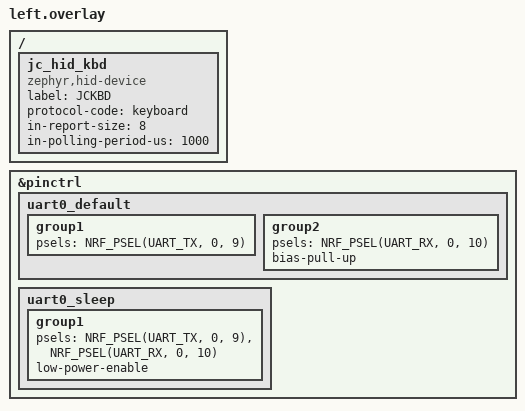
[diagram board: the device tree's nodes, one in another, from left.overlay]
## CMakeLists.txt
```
cmake_minimum_required(VERSION 3.20.0)

if(JC_LEFT)
  list(APPEND EXTRA_DTC_OVERLAY_FILE "${CMAKE_CURRENT_LIST_DIR}/left.overlay")
  list(APPEND EXTRA_CONF_FILE "${CMAKE_CURRENT_LIST_DIR}/left.conf")
endif()
list(APPEND EXTRA_DTC_OVERLAY_FILE "${CMAKE_CURRENT_LIST_DIR}/clock_rc.overlay")
list(APPEND EXTRA_CONF_FILE "${CMAKE_CURRENT_LIST_DIR}/clock_rc.conf")
if(NOT JC_LEFT)
  list(APPEND EXTRA_DTC_OVERLAY_FILE "${CMAKE_CURRENT_LIST_DIR}/right.overlay")
  list(APPEND EXTRA_CONF_FILE "${CMAKE_CURRENT_LIST_DIR}/usb_name_right.conf")
endif()
list(APPEND EXTRA_CONF_FILE "${CMAKE_CURRENT_LIST_DIR}/tx_power.conf")

if(NOT DEFINED JC_OUT)
  set(JC_OUT "${CMAKE_CURRENT_LIST_DIR}/out")
endif()
if(JC_OUT)
  if(JC_LEFT)
    set(jc_uf2 "${JC_OUT}/xd2joy_LEFT.uf2")
  else()
    set(jc_uf2 "${JC_OUT}/xd2joy_RIGHT.uf2")
  endif()
  set_property(GLOBAL APPEND PROPERTY extra_post_build_commands
    COMMAND ${CMAKE_COMMAND} -E copy ${CMAKE_BINARY_DIR}/zephyr/zephyr.uf2 ${jc_uf2}
    COMMAND ${CMAKE_COMMAND} -E echo Firmware copied to ${jc_uf2})
endif()

find_package(Zephyr REQUIRED HINTS $ENV{ZEPHYR_BASE})
project(xd2joy)

file(READ "${ZEPHYR_BASE}/include/zephyr/bluetooth/hci_types.h" jc_hci)
string(REGEX MATCH "#define[ \t]+BT_HCI_LE_INTERVAL_MIN[ \t]+0x0004" jc_floor "${jc_hci}")
if(NOT jc_floor)
  message(FATAL_ERROR "Zephyr patch 1 is missing: BT_HCI_LE_INTERVAL_MIN in "
                      "include/zephyr/bluetooth/hci_types.h is not 0x0004 -- see "
                      "ZEPHYR_PATCHES.md at the top of this repository")
endif()

foreach(jc_patched
    subsys/bluetooth/controller/ll_sw/nordic/lll/lll_scan.c
    subsys/bluetooth/controller/ll_sw/ull_llcp_conn_upd.c)
  file(READ "${ZEPHYR_BASE}/${jc_patched}" jc_src)
  string(FIND "${jc_src}" "conn window patch" jc_at)
  if(jc_at EQUAL -1)
    message(FATAL_ERROR "Zephyr patch 2 is missing from ${jc_patched} -- see "
                        "ZEPHYR_PATCHES.md at the top of this repository")
  endif()
endforeach()
zephyr_compile_definitions(JC_CONN_WIN_OFFSET=4 JC_CONN_WIN_SIZE=3)

target_sources(app PRIVATE
    src/chip_addr.c
    src/console_keep.c
    src/main.c
    src/hci_user_ext.c)
target_include_directories(app PRIVATE
    ${ZEPHYR_BASE}/subsys/bluetooth/controller
    ${ZEPHYR_BASE}/subsys/bluetooth/controller/ll_sw/nordic)
target_include_directories(app PRIVATE ${ZEPHYR_BASE}/subsys/bluetooth)
zephyr_include_directories(src)

if(JC_LEFT)
  target_compile_definitions(app PRIVATE JC_LEFT=1)
  target_sources(app PRIVATE src/usb_dev.c)
endif()
```

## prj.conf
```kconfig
CONFIG_BT=y
CONFIG_BT_PERIPHERAL=y
CONFIG_BT_DEVICE_NAME="Joy-Con 2 (R)"

CONFIG_BT_L2CAP_TX_MTU=512
CONFIG_BT_BUF_ACL_RX_SIZE=520
CONFIG_BT_BUF_ACL_TX_SIZE=251
CONFIG_BT_ATT_PREPARE_COUNT=2

CONFIG_BT_GATT_SERVICE_CHANGED=n
CONFIG_BT_GATT_CACHING=n

CONFIG_PRINTK=y

CONFIG_BT_GAP_PERIPHERAL_PREF_PARAMS=n

CONFIG_BT_HCI_VS=y
CONFIG_BT_DEVICE_NAME="Joy-Con 2 (R)"

CONFIG_BT_CTLR_TX_PWR_PLUS_4=y

CONFIG_BT_CTLR_CONN_INTERVAL_LOW_LATENCY=n
CONFIG_BT_CONN_PARAM_ANY=y
CONFIG_BT_CTLR_ADVANCED_FEATURES=y
CONFIG_BT_GAP_AUTO_UPDATE_CONN_PARAMS=n

CONFIG_BT_SMP=y

CONFIG_BT_GATT_CLIENT=y
CONFIG_BT_GATT_AUTO_UPDATE_MTU=n

CONFIG_BT_CTLR_DATA_LENGTH_MAX=251

CONFIG_BT_CTLR_USER_EXT=y
CONFIG_BT_CTLR_USER_CPR_INTERVAL_MIN=y

CONFIG_BT_CENTRAL=y
CONFIG_BT_OBSERVER=y
CONFIG_BT_MAX_CONN=2
CONFIG_BT_MAX_PAIRED=2
CONFIG_BT_GATT_AUTO_DISCOVER_CCC=y

CONFIG_BT_SMP_ENFORCE_MITM=n

CONFIG_BT_SMP_SC_PAIR_ONLY=n

CONFIG_LOG=n
CONFIG_BT_SMP_LOG_LEVEL_DBG=n

CONFIG_BT_SCAN_WITH_IDENTITY=y

CONFIG_BT_RX_STACK_SIZE=3072
CONFIG_MAIN_STACK_SIZE=2048
CONFIG_SYSTEM_WORKQUEUE_STACK_SIZE=3072

CONFIG_THREAD_ANALYZER=n
CONFIG_RESET_ON_FATAL_ERROR=n

CONFIG_SERIAL=y
CONFIG_UART_INTERRUPT_DRIVEN=y

CONFIG_BT_ATT_TX_COUNT=10

CONFIG_BT_BUF_ACL_TX_COUNT=12
CONFIG_BT_L2CAP_TX_BUF_COUNT=12
CONFIG_BT_BUF_EVT_RX_COUNT=16

CONFIG_BT_SETTINGS=y
CONFIG_FLASH=y
CONFIG_FLASH_MAP=y
CONFIG_FLASH_PAGE_LAYOUT=y
CONFIG_NVS=y
CONFIG_SETTINGS=y

CONFIG_MPU_ALLOW_FLASH_WRITE=y
```

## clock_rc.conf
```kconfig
CONFIG_CLOCK_CONTROL_NRF_K32SRC_RC_CALIBRATION=y

CONFIG_CLOCK_CONTROL_NRF_CALIBRATION_PERIOD=4000
CONFIG_CLOCK_CONTROL_NRF_CALIBRATION_MAX_SKIP=1
CONFIG_CLOCK_CONTROL_NRF_CALIBRATION_TEMP_DIFF=2
```

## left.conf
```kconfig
CONFIG_CDC_ACM_SERIAL_INITIALIZE_AT_BOOT=n

CONFIG_USBD_HID_SUPPORT=y
```

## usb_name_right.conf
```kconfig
CONFIG_CDC_ACM_SERIAL_MANUFACTURER_STRING="XD2Joy"
CONFIG_CDC_ACM_SERIAL_PRODUCT_STRING="XD2Joy (right)"
```

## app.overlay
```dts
&uicr {
	nfct-pins-as-gpios;
};

#include <zephyr/dt-bindings/pinctrl/nrf-pinctrl.h>

&pinctrl {
	uart0_default: uart0_default {
		group1 {
			psels = <NRF_PSEL(UART_TX, 0, 9)>;
		};
		group2 {
			psels = <NRF_PSEL(UART_RX, 0, 10)>;
			bias-pull-up;
		};
	};

	uart0_sleep: uart0_sleep {
		group1 {
			psels = <NRF_PSEL(UART_TX, 0, 9)>,
				<NRF_PSEL(UART_RX, 0, 10)>;
			low-power-enable;
		};
	};
};
```

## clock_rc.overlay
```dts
&lfclk {
	k32src = "rc";
	k32src-accuracy-ppm = <500>;
};
```

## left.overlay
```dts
#include <zephyr/dt-bindings/pinctrl/nrf-pinctrl.h>

&pinctrl {
	uart0_default: uart0_default {
		group1 {
			psels = <NRF_PSEL(UART_TX, 0, 9)>;
		};
		group2 {
			psels = <NRF_PSEL(UART_RX, 0, 10)>;
			bias-pull-up;
		};
	};

	uart0_sleep: uart0_sleep {
		group1 {
			psels = <NRF_PSEL(UART_TX, 0, 9)>,
				<NRF_PSEL(UART_RX, 0, 10)>;
			low-power-enable;
		};
	};
};

/ {
	jc_hid_kbd: jc_hid_kbd {
		compatible = "zephyr,hid-device";
		label = "JCKBD";
		protocol-code = "keyboard";
		in-report-size = <8>;
		in-polling-period-us = <1000>;
	};
};
```

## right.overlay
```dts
#include <zephyr/dt-bindings/pinctrl/nrf-pinctrl.h>

&pinctrl {
	uart0_default: uart0_default {
		group1 {
			psels = <NRF_PSEL(UART_TX, 1, 4)>;
		};
		group2 {
			psels = <NRF_PSEL(UART_RX, 1, 6)>;
			bias-pull-up;
		};
	};

	uart0_sleep: uart0_sleep {
		group1 {
			psels = <NRF_PSEL(UART_TX, 1, 4)>,
				<NRF_PSEL(UART_RX, 1, 6)>;
			low-power-enable;
		};
	};
};

&i2c1 {
	status = "disabled";
};
```

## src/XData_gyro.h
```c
#pragma once

#define ROT_PLAY_AT 0x0D
#define ROT_PLAY_LEN 43

static const uint8_t ROT_PLAY[89][ROT_PLAY_LEN] = {
  { 0xFF, 0x00, 0x28, 0x76, 0xB9, 0x02, 0x0F, 0x83, 0x76, 0x8F, 0x56, 0x48, 0x09, 0x59, 0xAA, 0x02, 0x05, 0xF8, 0x05, 0xD7, 0x4F, 0x02, 0xC0, 0xF4, 0xBF, 0xFC, 0x3F, 0x0B, 0xF8, 0x05, 0xF1, 0xA7, 0x01, 0x40, 0xFF, 0xFF, 0xFD, 0x9F, 0x0B, 0x00, 0x0C, 0xDA, 0x9F },
  { 0xFF, 0x00, 0x28, 0xA0, 0xA9, 0x02, 0x0F, 0x63, 0x84, 0x8F, 0xAA, 0x43, 0x89, 0xEF, 0xA9, 0x72, 0x05, 0x04, 0x06, 0xE8, 0x0F, 0x01, 0x40, 0xF4, 0x7F, 0xFD, 0xBF, 0x0A, 0x00, 0x06, 0xEE, 0x27, 0x01, 0x80, 0xFA, 0xFF, 0xFE, 0x1F, 0x0B, 0x00, 0x0C, 0xB8, 0x9F },
  { 0xFF, 0x00, 0x28, 0xCA, 0xA9, 0x02, 0x0F, 0x83, 0x8A, 0x8F, 0x46, 0x3E, 0x89, 0x8E, 0xA9, 0x92, 0x05, 0xF8, 0x05, 0xE0, 0xCF, 0x02, 0x40, 0xFD, 0x7F, 0xFC, 0x3F, 0x0B, 0x00, 0x06, 0xF4, 0xC7, 0x00, 0xC0, 0xFB, 0x9F, 0xFE, 0xBF, 0x0A, 0x08, 0x0C, 0xD4, 0x9F },
  { 0xFF, 0x00, 0x28, 0xF5, 0xB9, 0x02, 0x0F, 0x63, 0x94, 0x8F, 0x32, 0x38, 0x89, 0x16, 0xA9, 0x52, 0x05, 0xFC, 0x05, 0xE2, 0x0F, 0x04, 0x80, 0xFC, 0xBF, 0xFC, 0xFF, 0x0A, 0xF8, 0x05, 0xED, 0x07, 0x01, 0xE0, 0xFC, 0x7F, 0xFE, 0xBF, 0x0A, 0x08, 0x0C, 0xB6, 0x9F },
  { 0xFF, 0x00, 0x28, 0x1F, 0xAA, 0x02, 0x0F, 0xA3, 0x9C, 0x8F, 0x6E, 0x31, 0x09, 0x92, 0xA8, 0x42, 0x05, 0x08, 0x06, 0xE8, 0x8F, 0x02, 0xC0, 0xFA, 0xBF, 0xFC, 0x7F, 0x0B, 0x08, 0x06, 0xF4, 0xC7, 0x00, 0xA0, 0xFF, 0x3F, 0xFE, 0x5F, 0x0B, 0xF8, 0x0B, 0xCC, 0x9F },
  { 0xFF, 0x00, 0x28, 0x47, 0x8A, 0x02, 0x0F, 0x43, 0xAA, 0x8F, 0x5E, 0x2E, 0x89, 0x4C, 0xA8, 0x52, 0x05, 0xF4, 0x05, 0xDC, 0xCF, 0x01, 0x40, 0xF5, 0x3F, 0xFD, 0x7F, 0x0A, 0xF8, 0x05, 0xED, 0xA7, 0x00, 0xE0, 0xFA, 0x9F, 0xFE, 0xDF, 0x0A, 0x08, 0x0C, 0xCC, 0x9F },
  { 0xFF, 0x00, 0x28, 0x72, 0xBA, 0x02, 0x0F, 0x23, 0xB2, 0x8F, 0xCE, 0x27, 0x89, 0xC3, 0xA7, 0x72, 0x05, 0x04, 0x06, 0xEB, 0x4F, 0x02, 0x80, 0xFB, 0x7F, 0xFC, 0xFF, 0x0A, 0x00, 0x06, 0xF0, 0xC7, 0x00, 0xE0, 0xFC, 0x5F, 0xFE, 0xDF, 0x0A, 0xF0, 0x0B, 0xBA, 0x9F },
  { 0xFF, 0x00, 0x28, 0x9C, 0xAA, 0x02, 0x0F, 0x63, 0xB9, 0x8F, 0x62, 0x23, 0x89, 0x67, 0xA7, 0x52, 0x05, 0x00, 0x06, 0xDC, 0x0F, 0x02, 0xC0, 0xF7, 0xFF, 0xFC, 0xFF, 0x0A, 0x00, 0x06, 0xF1, 0xE7, 0x00, 0xC0, 0xFC, 0x7F, 0xFE, 0xFF, 0x0A, 0x10, 0x0C, 0xD6, 0x9F },
  { 0xFF, 0x00, 0x28, 0xC7, 0xBA, 0x02, 0x0F, 0x63, 0xC5, 0x8F, 0xBE, 0x1D, 0x89, 0xF3, 0xA6, 0x62, 0x05, 0x00, 0x06, 0xE6, 0xCF, 0x02, 0x40, 0xFA, 0xBF, 0xFC, 0xFF, 0x0A, 0x00, 0x06, 0xED, 0x47, 0x01, 0x40, 0xFB, 0x9F, 0xFE, 0x9F, 0x0A, 0x00, 0x0C, 0xBA, 0x9F },
  { 0xFF, 0x00, 0x28, 0xF1, 0xAA, 0x02, 0x0F, 0xC3, 0xCD, 0x8F, 0xB6, 0x16, 0x09, 0x76, 0xA6, 0x72, 0x05, 0x00, 0x06, 0xE4, 0x8F, 0x01, 0x80, 0xFC, 0xBF, 0xFC, 0x3F, 0x0B, 0x00, 0x06, 0xF4, 0x47, 0x01, 0xE0, 0xFE, 0x7F, 0xFE, 0x1F, 0x0B, 0x00, 0x0C, 0xCC, 0x9F },
  { 0xFF, 0x00, 0x28, 0x1B, 0xAB, 0x02, 0x0F, 0xA3, 0xD8, 0x8F, 0x76, 0x13, 0x09, 0x33, 0xA6, 0x52, 0x05, 0xFC, 0x05, 0xE2, 0xCF, 0x01, 0xC0, 0xF6, 0xFF, 0xFC, 0xFF, 0x0A, 0x00, 0x06, 0xEF, 0x07, 0x01, 0xA0, 0xFB, 0x3F, 0xFE, 0xDF, 0x0A, 0x08, 0x0C, 0xC4, 0x9F },
  { 0xFF, 0x00, 0x28, 0x45, 0xAB, 0x02, 0x0F, 0x23, 0xE1, 0x8F, 0x26, 0x0D, 0x09, 0xAB, 0xA5, 0x72, 0x05, 0x08, 0x06, 0xE9, 0xCF, 0x02, 0x80, 0xFC, 0xBF, 0xFC, 0xFF, 0x0A, 0x08, 0x06, 0xF3, 0xE7, 0x00, 0x80, 0xFC, 0x5F, 0xFE, 0x9F, 0x0A, 0x00, 0x0C, 0xBE, 0x9F },
  { 0xFF, 0x00, 0x28, 0x70, 0xBB, 0x02, 0x0F, 0xC3, 0xE7, 0x8F, 0x86, 0x06, 0x09, 0x28, 0xA5, 0x42, 0x05, 0x00, 0x06, 0xDE, 0xCF, 0x02, 0x00, 0xFB, 0x3F, 0xFC, 0x3F, 0x0B, 0x00, 0x06, 0xF3, 0x67, 0x01, 0xA0, 0xFE, 0x3F, 0xFE, 0x1F, 0x0B, 0x00, 0x0C, 0xCC, 0x9F },
  { 0xFF, 0x00, 0x28, 0x98, 0x8B, 0x02, 0x0F, 0x23, 0xF4, 0x8F, 0x36, 0x03, 0x09, 0xDE, 0xA4, 0x52, 0x05, 0x00, 0x06, 0xE5, 0x0F, 0x02, 0x40, 0xF7, 0x7F, 0xFD, 0xFF, 0x0A, 0xF8, 0x05, 0xEF, 0xE7, 0x00, 0x20, 0xFB, 0x7F, 0xFE, 0xBF, 0x0A, 0xF0, 0x0B, 0xC0, 0x9F },
  { 0xFF, 0x00, 0x28, 0xC2, 0xAB, 0x02, 0x0F, 0xA3, 0xFC, 0x8F, 0xBE, 0xFC, 0x08, 0x5F, 0xA4, 0x62, 0x05, 0xFC, 0x05, 0xE4, 0x0F, 0x02, 0x00, 0xFA, 0xBF, 0xFC, 0xFF, 0x0A, 0x08, 0x06, 0xF3, 0xA7, 0x00, 0x80, 0xFC, 0x7F, 0xFE, 0xFF, 0x0A, 0x10, 0x0C, 0xCA, 0x9F },
  { 0xFF, 0x00, 0x28, 0xED, 0xBB, 0x02, 0x0F, 0x63, 0x05, 0x90, 0x32, 0xF7, 0x88, 0xED, 0xA3, 0x72, 0x05, 0xFC, 0x05, 0xE2, 0x4F, 0x03, 0x40, 0xFB, 0x3F, 0xFD, 0x3F, 0x0B, 0xF8, 0x05, 0xEF, 0x47, 0x01, 0x00, 0xFD, 0x7F, 0xFE, 0xBF, 0x0A, 0xF0, 0x0B, 0xC2, 0x9F },
  { 0xFF, 0x00, 0x28, 0x17, 0xAC, 0x02, 0x0F, 0xC3, 0x0E, 0x90, 0x72, 0xF2, 0x08, 0x9A, 0xA3, 0x62, 0x05, 0x04, 0x06, 0xE6, 0xCF, 0x01, 0xC0, 0xFA, 0xBF, 0xFC, 0xFF, 0x0A, 0x00, 0x06, 0xF3, 0x47, 0x01, 0x20, 0xFD, 0x3F, 0xFE, 0xFF, 0x0A, 0x08, 0x0C, 0xC2, 0x9F },
  { 0xFF, 0x00, 0x28, 0x41, 0xAC, 0x02, 0x0F, 0xC3, 0x1A, 0x90, 0xF2, 0xEC, 0x88, 0x27, 0xA3, 0x72, 0x05, 0xFC, 0x05, 0xDD, 0x0F, 0x03, 0x00, 0xFA, 0xBF, 0xFC, 0xFF, 0x0A, 0x00, 0x06, 0xF1, 0x07, 0x01, 0x60, 0xFC, 0x3F, 0xFE, 0xFF, 0x0A, 0x08, 0x0C, 0xC6, 0x9F },
  { 0xFF, 0x00, 0x28, 0x6C, 0xBC, 0x02, 0x0F, 0x63, 0x22, 0x90, 0x56, 0xE8, 0x08, 0xC7, 0xA2, 0x82, 0x05, 0x04, 0x06, 0xE6, 0x0F, 0x02, 0x40, 0xFA, 0xFF, 0xFC, 0x3F, 0x0B, 0x00, 0x06, 0xF1, 0x87, 0x01, 0x40, 0xFE, 0x5F, 0xFE, 0xDF, 0x0A, 0xF8, 0x0B, 0xBE, 0x9F },
  { 0xFF, 0x00, 0x28, 0x96, 0xAC, 0x02, 0x0F, 0x83, 0x2E, 0x90, 0xA2, 0xE2, 0x88, 0x56, 0xA2, 0x52, 0x05, 0xFC, 0x05, 0xE1, 0x4F, 0x02, 0x80, 0xF6, 0xBF, 0xFC, 0xBF, 0x0A, 0x00, 0x06, 0xF1, 0xE7, 0x00, 0xC0, 0xFC, 0x7F, 0xFE, 0x1F, 0x0B, 0x08, 0x0C, 0xCE, 0x9F },
  { 0xFF, 0x00, 0x28, 0xC0, 0xAC, 0x02, 0x0F, 0x63, 0x38, 0x90, 0xAA, 0xDC, 0x08, 0xDF, 0xA1, 0x72, 0x05, 0x00, 0x06, 0xE2, 0x8F, 0x02, 0x80, 0xF9, 0x7F, 0xFC, 0xFF, 0x0A, 0x08, 0x06, 0xF0, 0x07, 0x01, 0x00, 0xFC, 0x5F, 0xFE, 0xFF, 0x0A, 0xF8, 0x0B, 0xBE, 0x9F },
  { 0xFF, 0x00, 0x28, 0xE9, 0x9C, 0x02, 0x0F, 0x23, 0x3F, 0x90, 0x92, 0xD7, 0x88, 0x78, 0xA1, 0x82, 0x05, 0x04, 0x06, 0xE4, 0xCF, 0x02, 0xC0, 0xFA, 0x7F, 0xFC, 0x3F, 0x0B, 0x00, 0x06, 0xF3, 0x47, 0x01, 0xA0, 0xFD, 0x5F, 0xFE, 0xDF, 0x0A, 0x10, 0x0C, 0xC8, 0x9F },
  { 0xFF, 0x00, 0x28, 0x13, 0xAD, 0x02, 0x0F, 0x23, 0x4D, 0x90, 0x2E, 0xD2, 0x08, 0x0B, 0xA1, 0x62, 0x05, 0xFC, 0x05, 0xDF, 0xCF, 0x01, 0x00, 0xF7, 0xFF, 0xFC, 0xFF, 0x0A, 0x00, 0x06, 0xEF, 0x47, 0x01, 0x60, 0xFB, 0x7F, 0xFE, 0xFF, 0x0A, 0x18, 0x0C, 0xC8, 0x9F },
  { 0xFF, 0x00, 0x28, 0x3D, 0xAD, 0x02, 0x0F, 0x43, 0x56, 0x90, 0x82, 0xCC, 0x88, 0x9A, 0xA0, 0x72, 0x05, 0x04, 0x06, 0xE6, 0x8F, 0x02, 0x80, 0xFD, 0xBF, 0xFC, 0x3F, 0x0B, 0x08, 0x06, 0xF0, 0x67, 0x01, 0xE0, 0xFC, 0x5F, 0xFE, 0x9F, 0x0A, 0xF8, 0x0B, 0xC0, 0x9F },
  { 0xFF, 0x00, 0x28, 0x68, 0xBD, 0x02, 0x0F, 0x23, 0x5D, 0x90, 0x5E, 0xC7, 0x08, 0x31, 0xA0, 0x52, 0x05, 0x00, 0x06, 0xDF, 0xCF, 0x01, 0xC0, 0xF7, 0xBF, 0xFC, 0x3F, 0x0B, 0x00, 0x06, 0xF1, 0xE7, 0x00, 0x80, 0xFE, 0x5F, 0xFE, 0x1F, 0x0B, 0x00, 0x0C, 0xCE, 0x9F },
  { 0xFF, 0x00, 0x28, 0x92, 0xAD, 0x02, 0x0F, 0x63, 0x6A, 0x90, 0x2A, 0xC2, 0x08, 0xC3, 0x9F, 0x52, 0x05, 0xFC, 0x05, 0xE4, 0xCF, 0x01, 0x00, 0xF8, 0xBF, 0xFC, 0xFF, 0x0A, 0xF8, 0x05, 0xEF, 0x07, 0x01, 0x80, 0xFB, 0x5F, 0xFE, 0xBF, 0x0A, 0x00, 0x0C, 0xC2, 0x9F },
  { 0xFF, 0x00, 0x28, 0xBC, 0xAD, 0x02, 0x0F, 0xC3, 0x70, 0x90, 0x2A, 0xBD, 0x08, 0x60, 0x9F, 0x62, 0x05, 0x00, 0x06, 0xE3, 0x4F, 0x02, 0x00, 0xFB, 0x3F, 0xFD, 0x3F, 0x0B, 0x00, 0x06, 0xF2, 0x67, 0x01, 0x40, 0xFD, 0x5F, 0xFE, 0x1F, 0x0B, 0xF8, 0x0B, 0xC4, 0x9F },
  { 0xFF, 0x00, 0x28, 0xE7, 0xBD, 0x02, 0x0F, 0x83, 0x7C, 0x90, 0x42, 0xB7, 0x08, 0xEC, 0x9E, 0x52, 0x05, 0x04, 0x06, 0xE1, 0x4F, 0x02, 0xC0, 0xF7, 0xFF, 0xFC, 0xBF, 0x0A, 0x00, 0x06, 0xF0, 0x47, 0x01, 0x80, 0xFD, 0x3F, 0xFE, 0xFF, 0x0A, 0x08, 0x0C, 0xC8, 0x9F },
  { 0xFF, 0x00, 0x28, 0x11, 0xAE, 0x02, 0x0F, 0xE3, 0x88, 0x90, 0xCE, 0xB1, 0x08, 0x7B, 0x9E, 0x52, 0x05, 0x00, 0x06, 0xE5, 0x8F, 0x02, 0x40, 0xF8, 0xFF, 0xFC, 0xFF, 0x0A, 0x00, 0x06, 0xF1, 0xC7, 0x00, 0xE0, 0xFA, 0xFF, 0xFE, 0xBF, 0x0A, 0xF0, 0x0B, 0xC0, 0x9F },
  { 0xFF, 0x00, 0x28, 0x39, 0x8E, 0x02, 0x0F, 0xA3, 0x8E, 0x90, 0x76, 0xAC, 0x08, 0x18, 0x9E, 0x62, 0x05, 0x00, 0x06, 0xE0, 0xCF, 0x02, 0x00, 0xFB, 0x7F, 0xFC, 0xFF, 0x0A, 0x00, 0x06, 0xF1, 0x07, 0x01, 0x20, 0xFD, 0x9F, 0xFE, 0xFF, 0x0A, 0x08, 0x0C, 0xCA, 0x9F },
  { 0xFF, 0x00, 0x28, 0x64, 0xBE, 0x02, 0x0F, 0x83, 0x9A, 0x90, 0x9A, 0xA6, 0x08, 0xA3, 0x9D, 0x72, 0x05, 0x00, 0x06, 0xE4, 0x0F, 0x03, 0xC0, 0xF9, 0x3F, 0xFD, 0x3F, 0x0B, 0x00, 0x06, 0xF0, 0xA7, 0x00, 0x20, 0xFD, 0x5F, 0xFE, 0xFF, 0x0A, 0xF8, 0x0B, 0xC6, 0x9F },
  { 0xFF, 0x00, 0x28, 0x8E, 0xAE, 0x02, 0x0F, 0x83, 0xA5, 0x90, 0x5E, 0xA1, 0x08, 0x3D, 0x9D, 0x62, 0x05, 0x00, 0x06, 0xE3, 0x8F, 0x01, 0x40, 0xFA, 0xFF, 0xFC, 0xBF, 0x0A, 0x00, 0x06, 0xF2, 0xC7, 0x00, 0x20, 0xFC, 0xBF, 0xFE, 0x9F, 0x0A, 0x10, 0x0C, 0xC8, 0x9F },
  { 0xFF, 0x00, 0x28, 0xB9, 0xBE, 0x02, 0x0F, 0xA3, 0xAA, 0x90, 0x1A, 0x9C, 0x88, 0xD0, 0x9C, 0x42, 0x05, 0x04, 0x06, 0xE1, 0x8F, 0x02, 0x00, 0xFA, 0xBF, 0xFC, 0xFF, 0x0A, 0x00, 0x06, 0xF1, 0x67, 0x01, 0xE0, 0xFD, 0x7F, 0xFE, 0xFF, 0x0A, 0xF8, 0x0B, 0xC4, 0x9F },
  { 0xFF, 0x00, 0x28, 0xE3, 0xAE, 0x02, 0x0F, 0x43, 0xB5, 0x90, 0xE6, 0x95, 0x88, 0x53, 0x9C, 0x62, 0x05, 0x00, 0x06, 0xE3, 0x4F, 0x02, 0xC0, 0xF9, 0x7F, 0xFC, 0xFF, 0x0A, 0xF8, 0x05, 0xF2, 0xE7, 0x00, 0x80, 0xFD, 0x9F, 0xFE, 0x1F, 0x0B, 0x00, 0x0C, 0xC4, 0x9F },
  { 0xFF, 0x00, 0x28, 0x0D, 0xAF, 0x02, 0x0F, 0x63, 0xC1, 0x90, 0x1A, 0x91, 0x08, 0xF1, 0x9B, 0x62, 0x05, 0xFC, 0x05, 0xE1, 0xCF, 0x01, 0x00, 0xF7, 0xBF, 0xFC, 0x7F, 0x0A, 0x00, 0x06, 0xEF, 0x87, 0x00, 0xA0, 0xFB, 0xFF, 0xFE, 0xBF, 0x0A, 0x00, 0x0C, 0xC8, 0x9F },
  { 0xFF, 0x00, 0x28, 0x37, 0xAF, 0x02, 0x0F, 0x03, 0xC8, 0x90, 0xC2, 0x8B, 0x08, 0x89, 0x9B, 0x62, 0x05, 0x00, 0x06, 0xE4, 0xCF, 0x02, 0x00, 0xFB, 0xBF, 0xFC, 0xFF, 0x0A, 0x00, 0x06, 0xF1, 0x27, 0x01, 0xE0, 0xFC, 0x1F, 0xFE, 0xDF, 0x0A, 0x08, 0x0C, 0xC0, 0x9F },
  { 0xFF, 0x00, 0x28, 0x62, 0xBF, 0x02, 0x0F, 0x23, 0xD3, 0x90, 0x86, 0x85, 0x08, 0x09, 0x9B, 0x62, 0x05, 0xFC, 0x05, 0xE4, 0x0F, 0x02, 0x80, 0xF8, 0xFF, 0xFC, 0xFF, 0x0A, 0x08, 0x06, 0xF2, 0x27, 0x01, 0xC0, 0xFC, 0x5F, 0xFE, 0xFF, 0x0A, 0x00, 0x0C, 0xCC, 0x9F },
  { 0xFF, 0x00, 0x28, 0x8A, 0x8F, 0x02, 0x0F, 0xC3, 0xDB, 0x90, 0x5A, 0x81, 0x88, 0xB4, 0x9A, 0x72, 0x05, 0x04, 0x06, 0xE3, 0x0F, 0x02, 0x00, 0xFB, 0xFF, 0xFC, 0xFF, 0x0A, 0x00, 0x06, 0xF0, 0x07, 0x01, 0xC0, 0xFB, 0x7F, 0xFE, 0x9F, 0x0A, 0xF8, 0x0B, 0xC4, 0x9F },
  { 0xFF, 0x00, 0x28, 0xB5, 0xBF, 0x02, 0x0F, 0xE3, 0xE2, 0x90, 0xAE, 0x7A, 0x88, 0x2B, 0x9A, 0x62, 0x05, 0x00, 0x06, 0xE4, 0xCF, 0x02, 0x40, 0xFC, 0xBF, 0xFC, 0x3F, 0x0B, 0xF8, 0x05, 0xF2, 0x07, 0x01, 0x20, 0xFE, 0x5F, 0xFE, 0xDF, 0x0A, 0x08, 0x0C, 0xC8, 0x9F },
  { 0xFF, 0x00, 0x28, 0xE1, 0xCF, 0x02, 0x0F, 0x03, 0xEE, 0x90, 0xE2, 0x74, 0x88, 0xB6, 0x99, 0x62, 0x05, 0x00, 0x06, 0xE0, 0x0F, 0x02, 0xC0, 0xF7, 0x3F, 0xFD, 0x3F, 0x0B, 0x00, 0x06, 0xF1, 0xA7, 0x01, 0xC0, 0xFD, 0x5F, 0xFE, 0xDF, 0x0A, 0x00, 0x0C, 0xC6, 0x9F },
  { 0xFF, 0x00, 0x28, 0x09, 0x80, 0x02, 0x0F, 0xE3, 0xF6, 0x90, 0xD6, 0x70, 0x08, 0x68, 0x99, 0x62, 0x05, 0x00, 0x06, 0xE4, 0xCF, 0x01, 0x80, 0xF9, 0xBF, 0xFC, 0xBF, 0x0A, 0x00, 0x06, 0xF0, 0xC7, 0x00, 0xE0, 0xFB, 0x7F, 0xFE, 0xBF, 0x0A, 0x10, 0x0C, 0xC4, 0x9F },
  { 0xFF, 0x00, 0x28, 0x34, 0xB0, 0x02, 0x0F, 0xC3, 0xFE, 0x90, 0x12, 0x6A, 0x08, 0xDB, 0x98, 0x62, 0x05, 0x00, 0x06, 0xE2, 0xCF, 0x01, 0x40, 0xFA, 0xBF, 0xFC, 0x3F, 0x0B, 0x00, 0x06, 0xF2, 0xE7, 0x00, 0xE0, 0xFD, 0x7F, 0xFE, 0xFF, 0x0A, 0xF8, 0x0B, 0xC6, 0x9F },
  { 0xFF, 0x00, 0x28, 0x5E, 0xA0, 0x02, 0x0F, 0x23, 0x09, 0x91, 0x1A, 0x65, 0x08, 0x70, 0x98, 0x62, 0x05, 0x00, 0x06, 0xE1, 0x8F, 0x02, 0x00, 0xF8, 0xFF, 0xFC, 0xFF, 0x0A, 0x00, 0x06, 0xF0, 0xA7, 0x00, 0x80, 0xFC, 0xBF, 0xFE, 0xDF, 0x0A, 0x08, 0x0C, 0xC4, 0x9F },
  { 0xFF, 0x00, 0x28, 0x88, 0xA0, 0x02, 0x0F, 0xC3, 0x11, 0x91, 0x8E, 0x60, 0x88, 0x17, 0x98, 0x82, 0x05, 0xFC, 0x05, 0xE4, 0x8F, 0x02, 0x80, 0xFB, 0xBF, 0xFC, 0xFF, 0x0A, 0x00, 0x06, 0xF2, 0x07, 0x01, 0x40, 0xFC, 0x7F, 0xFE, 0xBF, 0x0A, 0x08, 0x0C, 0xC4, 0x9F },
  { 0xFF, 0x00, 0x28, 0xB3, 0xB0, 0x02, 0x0F, 0x63, 0x1B, 0x91, 0xEA, 0x59, 0x88, 0x8F, 0x97, 0x72, 0x05, 0x04, 0x06, 0xE2, 0x0F, 0x02, 0x00, 0xFC, 0xBF, 0xFC, 0x3F, 0x0B, 0x00, 0x06, 0xF1, 0x07, 0x01, 0x40, 0xFE, 0x9F, 0xFE, 0x1F, 0x0B, 0x08, 0x0C, 0xC4, 0x9F },
  { 0xFF, 0x00, 0x28, 0xDB, 0x80, 0x02, 0x0F, 0xC3, 0x26, 0x91, 0x76, 0x55, 0x88, 0x33, 0x97, 0x72, 0x05, 0x04, 0x06, 0xE2, 0x4F, 0x02, 0xC0, 0xF9, 0x3F, 0xFD, 0xFF, 0x0A, 0x00, 0x06, 0xF1, 0xE7, 0x00, 0x20, 0xFD, 0x1F, 0xFE, 0xDF, 0x0A, 0x08, 0x0C, 0xC4, 0x9F },
  { 0xFF, 0x00, 0x28, 0x05, 0xA1, 0x02, 0x0F, 0xE3, 0x30, 0x91, 0x92, 0x50, 0x88, 0xD2, 0x96, 0x62, 0x05, 0x00, 0x06, 0xE2, 0x0F, 0x03, 0x80, 0xFB, 0xBF, 0xFC, 0xFF, 0x0A, 0xF8, 0x05, 0xF1, 0x87, 0x01, 0xC0, 0xFC, 0x7F, 0xFE, 0xBF, 0x0A, 0x00, 0x0C, 0xC6, 0x9F },
  { 0xFF, 0x00, 0x28, 0x30, 0xB1, 0x02, 0x0F, 0xA3, 0x3B, 0x91, 0x22, 0x4A, 0x08, 0x58, 0x96, 0x52, 0x05, 0x04, 0x06, 0xE1, 0x8F, 0x02, 0x00, 0xFA, 0xBF, 0xFC, 0x3F, 0x0B, 0x00, 0x06, 0xF0, 0x27, 0x01, 0xC0, 0xFD, 0x3F, 0xFE, 0xFF, 0x0A, 0x00, 0x0C, 0xC2, 0x9F },
  { 0xFF, 0x00, 0x28, 0x5A, 0xA1, 0x02, 0x0F, 0x83, 0x47, 0x91, 0x42, 0x46, 0x08, 0x0B, 0x96, 0x62, 0x05, 0x00, 0x06, 0xE0, 0x8F, 0x01, 0x00, 0xF7, 0x3F, 0xFD, 0xFF, 0x0A, 0x08, 0x06, 0xF0, 0x27, 0x01, 0xE0, 0xFB, 0x5F, 0xFE, 0xBF, 0x0A, 0x00, 0x0C, 0xC4, 0x9F },
  { 0xFF, 0x00, 0x28, 0x84, 0xA1, 0x02, 0x0F, 0xC3, 0x51, 0x91, 0xB2, 0x3F, 0x88, 0x84, 0x95, 0x72, 0x05, 0x00, 0x06, 0xE3, 0x0F, 0x03, 0x40, 0xFA, 0xBF, 0xFC, 0xFF, 0x0A, 0x00, 0x06, 0xF1, 0x27, 0x01, 0x20, 0xFC, 0x9F, 0xFE, 0xFF, 0x0A, 0x10, 0x0C, 0xCA, 0x9F },
  { 0xFF, 0x00, 0x28, 0xAF, 0xB1, 0x02, 0x0F, 0x23, 0x5C, 0x91, 0x62, 0x39, 0x88, 0x0C, 0x95, 0x62, 0x05, 0x04, 0x06, 0xE3, 0x8F, 0x02, 0x80, 0xFB, 0xFF, 0xFC, 0x3F, 0x0B, 0xF8, 0x05, 0xF1, 0x67, 0x01, 0x60, 0xFD, 0x7F, 0xFE, 0x3F, 0x0B, 0x10, 0x0C, 0xC8, 0x9F },
  { 0xFF, 0x00, 0x28, 0xD9, 0xA1, 0x02, 0x0F, 0x63, 0x66, 0x91, 0x2A, 0x35, 0x88, 0xB5, 0x94, 0x72, 0x05, 0x00, 0x06, 0xE2, 0xCF, 0x02, 0x80, 0xF8, 0xBF, 0xFC, 0xFF, 0x0A, 0x00, 0x06, 0xF1, 0x07, 0x01, 0x00, 0xFC, 0xBF, 0xFE, 0xDF, 0x0A, 0x18, 0x0C, 0xC8, 0x9F },
  { 0xFF, 0x00, 0x28, 0x03, 0xA2, 0x02, 0x0F, 0x63, 0x72, 0x91, 0x8E, 0x2E, 0x88, 0x31, 0x94, 0x82, 0x05, 0x04, 0x06, 0xE3, 0x0F, 0x02, 0x00, 0xFB, 0xFF, 0xFB, 0xFF, 0x0A, 0x08, 0x06, 0xF2, 0x47, 0x01, 0x60, 0xFC, 0x5F, 0xFE, 0xDF, 0x0A, 0x08, 0x0C, 0xC4, 0x9F },
  { 0xFF, 0x00, 0x28, 0x2C, 0x92, 0x02, 0x0F, 0x83, 0x7B, 0x91, 0x92, 0x28, 0x08, 0xBB, 0x93, 0x52, 0x05, 0x00, 0x06, 0xE3, 0xCF, 0x02, 0xC0, 0xFB, 0xBF, 0xFC, 0x3F, 0x0B, 0xF8, 0x05, 0xF2, 0x07, 0x01, 0xA0, 0xFE, 0x1F, 0xFE, 0x5F, 0x0B, 0xF8, 0x0B, 0xC6, 0x9F },
  { 0xFF, 0x00, 0x28, 0x56, 0xA2, 0x02, 0x0F, 0x63, 0x89, 0x91, 0xB2, 0x24, 0x88, 0x6B, 0x93, 0x62, 0x05, 0xFC, 0x05, 0xE3, 0x0F, 0x02, 0xC0, 0xF6, 0x3F, 0xFD, 0xFF, 0x0A, 0x00, 0x06, 0xF1, 0x47, 0x01, 0x40, 0xFC, 0xBF, 0xFE, 0xFF, 0x0A, 0xF0, 0x0B, 0xC8, 0x9F },
  { 0xFF, 0x00, 0x28, 0x80, 0xA2, 0x02, 0x0F, 0xA3, 0x93, 0x91, 0x6A, 0x1E, 0x88, 0xF8, 0x92, 0x72, 0x05, 0x00, 0x06, 0xE3, 0x0F, 0x02, 0x00, 0xF7, 0xFF, 0xFC, 0xFF, 0x0A, 0xF8, 0x05, 0xF0, 0xC7, 0x00, 0xA0, 0xFE, 0x1F, 0xFE, 0xDF, 0x0A, 0xF8, 0x0B, 0xC8, 0x9F },
  { 0xFF, 0x00, 0x28, 0xAB, 0xB2, 0x02, 0x0F, 0x63, 0x9D, 0x91, 0x72, 0x1A, 0x88, 0x9D, 0x92, 0x42, 0x05, 0x00, 0x06, 0xE0, 0x0F, 0x02, 0x80, 0xF5, 0x3F, 0xFD, 0xBF, 0x0A, 0x00, 0x06, 0xF2, 0x07, 0x01, 0xC0, 0xFA, 0x5F, 0xFE, 0xDF, 0x0A, 0x10, 0x0C, 0xC0, 0x9F },
  { 0xFF, 0x00, 0x28, 0xD5, 0xA2, 0x02, 0x0F, 0x23, 0xA9, 0x91, 0xAA, 0x13, 0x88, 0x15, 0x92, 0x82, 0x05, 0x04, 0x06, 0xE5, 0x4F, 0x01, 0xC0, 0xF8, 0xBF, 0xFC, 0xFF, 0x0A, 0x08, 0x06, 0xF1, 0x67, 0x00, 0xA0, 0xF9, 0xBF, 0xFE, 0x9F, 0x0A, 0x00, 0x0C, 0xC0, 0x9F },
  { 0xFF, 0x00, 0x28, 0xFF, 0xA2, 0x02, 0x0F, 0x43, 0xAF, 0x91, 0x8A, 0x0D, 0x08, 0x95, 0x91, 0x82, 0x05, 0xFC, 0x05, 0xE4, 0x0F, 0x03, 0x80, 0x00, 0x00, 0xFC, 0xFF, 0x0A, 0x00, 0x06, 0xF2, 0xA7, 0x01, 0x60, 0xFC, 0x7F, 0xFE, 0x7F, 0x0A, 0x10, 0x0C, 0xC0, 0x9F },
  { 0xFF, 0x00, 0x28, 0x2A, 0xB3, 0x02, 0x0F, 0x23, 0xB7, 0x91, 0x1E, 0x08, 0x08, 0x32, 0x91, 0x42, 0x05, 0x00, 0x06, 0xE1, 0x8F, 0x02, 0x00, 0xFA, 0xFF, 0xFC, 0x3F, 0x0B, 0x00, 0x06, 0xF2, 0x47, 0x01, 0x60, 0xFF, 0x5F, 0xFE, 0x1F, 0x0B, 0x00, 0x0C, 0xC6, 0x9F },
  { 0xFF, 0x00, 0x28, 0x54, 0xA3, 0x02, 0x0F, 0xE3, 0xC4, 0x91, 0xBA, 0x02, 0x08, 0xC7, 0x90, 0x42, 0x05, 0x04, 0x06, 0xE0, 0x8F, 0x01, 0x00, 0xF7, 0xFF, 0xFD, 0xFF, 0x0A, 0x00, 0x06, 0xF1, 0xE7, 0x00, 0xA0, 0xFC, 0x7F, 0xFE, 0xDF, 0x0A, 0x00, 0x0C, 0xC2, 0x9F },
  { 0xFF, 0x00, 0x28, 0x7C, 0x83, 0x02, 0x0F, 0xE3, 0xCD, 0x91, 0xCA, 0xFD, 0x07, 0x5E, 0x90, 0x72, 0x05, 0xFC, 0x05, 0xE3, 0x4F, 0x02, 0x00, 0xF9, 0xBF, 0xFC, 0xFF, 0x0A, 0x00, 0x06, 0xF1, 0x67, 0x01, 0x60, 0xFC, 0x7F, 0xFE, 0xBF, 0x0A, 0x00, 0x0C, 0xCA, 0x9F },
  { 0xFF, 0x00, 0x28, 0xA7, 0xB3, 0x02, 0x0F, 0x83, 0xD6, 0x91, 0x92, 0xF8, 0x87, 0xF6, 0x8F, 0x62, 0x05, 0xFC, 0x05, 0xE3, 0x0F, 0x02, 0xC0, 0xF8, 0xFF, 0xFC, 0xFF, 0x0A, 0x00, 0x06, 0xF1, 0x87, 0x01, 0xA0, 0xFB, 0x9F, 0xFE, 0xDF, 0x0A, 0x00, 0x0C, 0xC6, 0x9F },
  { 0xFF, 0x00, 0x28, 0xD1, 0xA3, 0x02, 0x0F, 0x83, 0xE3, 0x91, 0xA2, 0xF2, 0x87, 0x85, 0x8F, 0x82, 0x05, 0x00, 0x06, 0xE3, 0x8F, 0x02, 0xC0, 0xFA, 0xBF, 0xFC, 0xFF, 0x0A, 0x00, 0x06, 0xF1, 0xA7, 0x00, 0x40, 0xFC, 0x9F, 0xFE, 0xBF, 0x0A, 0xF8, 0x0B, 0xC4, 0x9F },
  { 0xFF, 0x00, 0x28, 0xFC, 0xB3, 0x02, 0x0F, 0x23, 0xE8, 0x91, 0xEA, 0xED, 0x87, 0x23, 0x8F, 0x62, 0x05, 0x00, 0x06, 0xE2, 0x0F, 0x02, 0x80, 0xFB, 0xFF, 0xFC, 0x3F, 0x0B, 0x00, 0x06, 0xF1, 0x67, 0x01, 0x40, 0xFE, 0x3F, 0xFE, 0xDF, 0x0A, 0x00, 0x0C, 0xC4, 0x9F },
  { 0xFF, 0x00, 0x28, 0x26, 0xA4, 0x02, 0x0F, 0x83, 0xF4, 0x91, 0x02, 0xE8, 0x07, 0xAD, 0x8E, 0x62, 0x05, 0x04, 0x06, 0xE3, 0xCF, 0x01, 0x00, 0xF6, 0xFF, 0xFC, 0xFF, 0x0A, 0x00, 0x06, 0xF0, 0x27, 0x01, 0x00, 0xFD, 0x5F, 0xFE, 0xFF, 0x0A, 0x00, 0x0C, 0xC8, 0x9F },
  { 0xFF, 0x00, 0x28, 0x50, 0xA4, 0x02, 0x0F, 0x43, 0xFF, 0x91, 0x3E, 0xE2, 0x07, 0x38, 0x8E, 0x82, 0x05, 0x04, 0x06, 0xE2, 0x0F, 0x02, 0x00, 0xFA, 0xBF, 0xFC, 0xFF, 0x0A, 0x00, 0x06, 0xF0, 0xA7, 0x00, 0x60, 0xFB, 0xBF, 0xFE, 0xBF, 0x0A, 0x10, 0x0C, 0xC4, 0x9F },
  { 0xFF, 0x00, 0x28, 0x7A, 0xA4, 0x02, 0x0F, 0x03, 0x06, 0x92, 0x4E, 0xDD, 0x87, 0xD6, 0x8D, 0x82, 0x05, 0x00, 0x06, 0xE3, 0x8F, 0x02, 0x00, 0xFC, 0x3F, 0xFC, 0xFF, 0x0A, 0x00, 0x06, 0xF1, 0xA7, 0x01, 0x00, 0xFE, 0x5F, 0xFE, 0xDF, 0x0A, 0xF8, 0x0B, 0xC2, 0x9F },
  { 0xFF, 0x00, 0x28, 0xA5, 0xB4, 0x02, 0x0F, 0xC3, 0x13, 0x92, 0x22, 0xD7, 0x07, 0x62, 0x8D, 0x52, 0x05, 0x00, 0x06, 0xE2, 0x8F, 0x01, 0xC0, 0xF7, 0xBF, 0xFD, 0xFF, 0x0A, 0xF8, 0x05, 0xF1, 0x47, 0x01, 0x00, 0xFD, 0x5F, 0xFE, 0x1F, 0x0B, 0x08, 0x0C, 0xC8, 0x9F },
  { 0xFF, 0x00, 0x28, 0xCD, 0x84, 0x02, 0x0F, 0x43, 0x1E, 0x92, 0xB6, 0xD1, 0x87, 0xF8, 0x8C, 0x72, 0x05, 0x04, 0x06, 0xE3, 0x8F, 0x02, 0xC0, 0xF9, 0x7F, 0xFC, 0xFF, 0x0A, 0x00, 0x06, 0xF1, 0x07, 0x01, 0x00, 0xFC, 0x7F, 0xFE, 0xDF, 0x0A, 0xF8, 0x0B, 0xC6, 0x9F },
  { 0xFF, 0x00, 0x28, 0xF7, 0xA4, 0x02, 0x0F, 0x63, 0x28, 0x92, 0x52, 0xCC, 0x07, 0x90, 0x8C, 0x72, 0x05, 0x00, 0x06, 0xE3, 0x8F, 0x01, 0xC0, 0xF9, 0xBF, 0xFC, 0x3F, 0x0B, 0x00, 0x06, 0xF1, 0x67, 0x01, 0x60, 0xFD, 0x7F, 0xFE, 0xFF, 0x0A, 0x08, 0x0C, 0xC8, 0x9F },
  { 0xFF, 0x00, 0x28, 0x22, 0xB5, 0x02, 0x0F, 0x63, 0x33, 0x92, 0x62, 0xC6, 0x07, 0x16, 0x8C, 0x62, 0x05, 0xFC, 0x05, 0xE4, 0x0F, 0x03, 0xC0, 0xF7, 0x3F, 0xFD, 0xFF, 0x0A, 0x00, 0x06, 0xF1, 0x27, 0x01, 0x60, 0xFC, 0x5F, 0xFE, 0xFF, 0x0A, 0xF8, 0x0B, 0xCA, 0x9F },
  { 0xFF, 0x00, 0x28, 0x4C, 0xA5, 0x02, 0x0F, 0xC3, 0x3B, 0x92, 0xEE, 0xC1, 0x07, 0xBF, 0x8B, 0x82, 0x05, 0xFC, 0x05, 0xE5, 0x8F, 0x02, 0x80, 0xFB, 0xBF, 0xFC, 0x3F, 0x0B, 0xF8, 0x05, 0xF1, 0x27, 0x01, 0x20, 0xFC, 0xDF, 0xFE, 0xDF, 0x0A, 0x08, 0x0C, 0xC6, 0x9F },
  { 0xFF, 0x00, 0x28, 0x76, 0xA5, 0x02, 0x0F, 0x23, 0x45, 0x92, 0x22, 0xBB, 0x87, 0x3D, 0x8B, 0x62, 0x05, 0x00, 0x06, 0xE2, 0x0F, 0x03, 0x00, 0xFC, 0xBF, 0xFC, 0x7F, 0x0B, 0x08, 0x06, 0xF2, 0x07, 0x01, 0x20, 0xFE, 0x5F, 0xFE, 0xFF, 0x0A, 0x08, 0x0C, 0xC8, 0x9F },
  { 0xFF, 0x00, 0x28, 0xA1, 0xB5, 0x02, 0x0F, 0x63, 0x51, 0x92, 0x66, 0xB5, 0x07, 0xC6, 0x8A, 0x52, 0x05, 0x00, 0x06, 0xE2, 0x4F, 0x02, 0x40, 0xF8, 0x3F, 0xFD, 0x3F, 0x0B, 0x00, 0x06, 0xF1, 0x07, 0x01, 0x40, 0xFD, 0x5F, 0xFE, 0xFF, 0x0A, 0x00, 0x0C, 0xC8, 0x9F },
  { 0xFF, 0x00, 0x28, 0xCB, 0xA5, 0x02, 0x0F, 0x63, 0x5A, 0x92, 0xFA, 0xB0, 0x87, 0x71, 0x8A, 0x72, 0x05, 0xFC, 0x05, 0xE3, 0xCF, 0x01, 0xC0, 0xF9, 0xFF, 0xFC, 0xFF, 0x0A, 0x00, 0x06, 0xF0, 0x07, 0x01, 0x80, 0xFC, 0x5F, 0xFE, 0xBF, 0x0A, 0x00, 0x0C, 0xC6, 0x9F },
  { 0xFF, 0x00, 0x28, 0xF5, 0xA5, 0x02, 0x0F, 0x43, 0x64, 0x92, 0x42, 0xAA, 0x87, 0xE9, 0x89, 0x72, 0x05, 0x00, 0x06, 0xE2, 0x8F, 0x02, 0xC0, 0xF9, 0x7F, 0xFC, 0xFF, 0x0A, 0x00, 0x06, 0xF1, 0x27, 0x01, 0x00, 0xFE, 0x5F, 0xFE, 0x3F, 0x0B, 0x10, 0x0C, 0xC6, 0x9F },
  { 0xFF, 0x00, 0x28, 0x1E, 0x96, 0x02, 0x0F, 0xE3, 0x70, 0x92, 0x2E, 0xA5, 0x87, 0x7A, 0x89, 0x52, 0x05, 0xFC, 0x05, 0xE2, 0x0F, 0x02, 0xC0, 0xF5, 0x7F, 0xFD, 0xFF, 0x0A, 0x00, 0x06, 0xF0, 0x47, 0x01, 0xE0, 0xFB, 0x5F, 0xFE, 0xBF, 0x0A, 0x08, 0x0C, 0xC6, 0x9F },
  { 0xFF, 0x00, 0x28, 0x48, 0xA6, 0x02, 0x0F, 0x43, 0x79, 0x92, 0xDE, 0x9F, 0x87, 0x11, 0x89, 0x82, 0x05, 0x00, 0x06, 0xE2, 0x4F, 0x02, 0x00, 0xFC, 0x7F, 0xFC, 0xFF, 0x0A, 0x00, 0x06, 0xF1, 0x07, 0x01, 0x40, 0xFC, 0x3F, 0xFE, 0xBF, 0x0A, 0x00, 0x0C, 0xC0, 0x9F },
  { 0xFF, 0x00, 0x28, 0x72, 0xA6, 0x02, 0x0F, 0x63, 0x84, 0x92, 0x5E, 0x99, 0x87, 0x8B, 0x88, 0x62, 0x05, 0x00, 0x06, 0xE1, 0x4F, 0x02, 0x40, 0xFB, 0xFF, 0xFC, 0xFF, 0x0A, 0x00, 0x06, 0xF2, 0x67, 0x01, 0xC0, 0xFD, 0x1F, 0xFE, 0x1F, 0x0B, 0xF8, 0x0B, 0xC6, 0x9F },
  { 0xFF, 0x00, 0x28, 0x9D, 0xB6, 0x02, 0x0F, 0x63, 0x8E, 0x92, 0xC6, 0x93, 0x87, 0x17, 0x88, 0x52, 0x05, 0xFC, 0x05, 0xE3, 0x4F, 0x02, 0x40, 0xF8, 0x3F, 0xFD, 0xBF, 0x0A, 0x08, 0x06, 0xF1, 0x07, 0x01, 0x60, 0xFC, 0x7F, 0xFE, 0xFF, 0x0A, 0x08, 0x0C, 0xC2, 0x9F },
  { 0xFF, 0x00, 0x28, 0xC7, 0xA6, 0x02, 0x0F, 0xE3, 0x96, 0x92, 0x8E, 0x8E, 0x87, 0xAF, 0x87, 0x62, 0x05, 0x00, 0x06, 0xE2, 0x4F, 0x03, 0x40, 0xFB, 0x7F, 0xFC, 0x3F, 0x0B, 0x00, 0x06, 0xF1, 0xE7, 0x00, 0x40, 0xFD, 0x7F, 0xFE, 0xFF, 0x0A, 0xF8, 0x0B, 0xC4, 0x9F },
  { 0xFF, 0x00, 0x28, 0xF1, 0xA6, 0x02, 0x0F, 0xE3, 0xA0, 0x92, 0x66, 0x88, 0x87, 0x34, 0x87, 0x52, 0x05, 0x00, 0x06, 0xE1, 0x0F, 0x02, 0x80, 0xFA, 0xBF, 0xFC, 0x3F, 0x0B, 0x00, 0x06, 0xF1, 0xA7, 0x01, 0x60, 0xFD, 0x7F, 0xFE, 0xDF, 0x0A, 0x00, 0x0C, 0xC4, 0x9F },
  { 0xFF, 0x00, 0x28, 0x1C, 0xB7, 0x02, 0x0F, 0xA3, 0xAA, 0x92, 0x6E, 0x84, 0x07, 0xE5, 0x86, 0x62, 0x05, 0x04, 0x06, 0xE3, 0x4F, 0x02, 0xC0, 0xF7, 0x3F, 0xFD, 0xFF, 0x0A, 0x00, 0x06, 0xF0, 0x67, 0x01, 0x00, 0xFC, 0x5F, 0xFE, 0xDF, 0x0A, 0x10, 0x0C, 0xC6, 0x9F },
  { 0xFF, 0x00, 0x28, 0x46, 0xA7, 0x02, 0x0F, 0x23, 0xB6, 0x92, 0xE6, 0x7D, 0x07, 0x62, 0x86, 0x72, 0x05, 0x00, 0x06, 0xE1, 0xCF, 0x02, 0xC0, 0xFA, 0x7F, 0xFD, 0xFF, 0x0A, 0x08, 0x06, 0xF2, 0x47, 0x00, 0x60, 0xFC, 0x5F, 0xFE, 0xFF, 0x0A, 0x08, 0x0C, 0xBC, 0x9F },
  { 0xFF, 0x00, 0x28, 0x6E, 0x87, 0x02, 0x0F, 0x43, 0xBE, 0x92, 0xFE, 0x77, 0x87, 0xEF, 0x85, 0x72, 0x05, 0x08, 0x06, 0xE6, 0xCF, 0x03, 0x00, 0xF8, 0xFF, 0xFC, 0xFF, 0x0A, 0x00, 0x06, 0xF2, 0xA7, 0x01, 0xA0, 0xFD, 0x5F, 0xFE, 0xFF, 0x0A, 0x08, 0x0C, 0xC6, 0x9F },
  { 0xFF, 0x00, 0x28, 0x99, 0xB7, 0x02, 0x0F, 0x03, 0xCB, 0x92, 0xD2, 0x72, 0x87, 0x99, 0x85, 0x62, 0x05, 0x00, 0x06, 0xE7, 0xCF, 0x00, 0x80, 0xFA, 0x3F, 0xFD, 0xFF, 0x0A, 0x00, 0x06, 0xF2, 0xC7, 0x00, 0x80, 0xFB, 0x7F, 0xFE, 0xFF, 0x0A, 0x00, 0x0C, 0xBC, 0x9F },
  { 0xFF, 0x00, 0x28, 0xC3, 0xA7, 0x02, 0x0F, 0x83, 0xD3, 0x92, 0xD6, 0x6C, 0x07, 0x15, 0x85, 0x72, 0x05, 0x04, 0x06, 0xE3, 0x0F, 0x03, 0x40, 0xFB, 0x7F, 0xFC, 0xFF, 0x0A, 0xF8, 0x05, 0xF6, 0x67, 0xFF, 0xDF, 0xFE, 0x5F, 0xFE, 0xBF, 0x0A, 0x08, 0x0C, 0xA8, 0x9F },
  { 0xFF, 0x00, 0x28, 0xEE, 0xB7, 0x02, 0x0F, 0xE3, 0xDC, 0x92, 0x92, 0x66, 0x87, 0xA0, 0x84, 0x52, 0x05, 0x00, 0x06, 0xE3, 0xCF, 0xFD, 0xFF, 0xFB, 0xBF, 0xFC, 0x3F, 0x0B, 0xF8, 0x05, 0xEE, 0x07, 0x03, 0xA0, 0xFD, 0x7F, 0xFE, 0x1F, 0x0B, 0x08, 0x0C, 0xD8, 0x9F },
};
```

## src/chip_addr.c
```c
#include <stdint.h>
#include <hal/nrf_ficr.h>

void chip_addr(uint8_t addr[6])
{
	const uint32_t id[2] = {
		nrf_ficr_deviceid_get(NRF_FICR, 1),
		nrf_ficr_deviceid_get(NRF_FICR, 0),
	};
	uint32_t h = 0x811C9DC5u;

	for (int w = 0; w < 2; w++) {
		for (int shift = 24; shift >= 0; shift -= 8) {
			h ^= (id[w] >> shift) & 0xFFu;
			h *= 0x01000193u;
		}
	}
	h = (h ^ (h >> 24)) & 0xFFFFFFu;

	addr[0] = h & 0xFFu;
	addr[1] = (h >> 8) & 0xFFu;
	addr[2] = (h >> 16) & 0xFFu;
	addr[3] = 0x70;
	addr[4] = 0x68;
	addr[5] = 0xB8;
}
```

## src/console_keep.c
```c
#include <zephyr/kernel.h>
#include <zephyr/settings/settings.h>
#include <zephyr/bluetooth/bluetooth.h>
#include <zephyr/bluetooth/conn.h>
#include <zephyr/bluetooth/hci.h>
#include <host/keys.h>
#include <string.h>
#include <errno.h>

#define PCON_VER 1
#define PCON_KEY "jc_con/rec"

struct pcon_rec {
	uint8_t ver;
	bt_addr_le_t addr;
	uint8_t ltk[16];
};

static struct pcon_rec to_save;
static struct pcon_rec loaded;
static bool loaded_ok;

static int pcon_set(const char *name, size_t len, settings_read_cb read_cb, void *cb_arg)
{
	const char *next;
	struct pcon_rec r;

	if (!settings_name_steq(name, "rec", &next) || next) {
		return -ENOENT;
	}
	if (len != sizeof(r) || read_cb(cb_arg, &r, sizeof(r)) != (ssize_t)sizeof(r) ||
	    r.ver != PCON_VER) {
		return 0;
	}
	loaded = r;
	loaded_ok = true;
	return 0;
}

SETTINGS_STATIC_HANDLER_DEFINE(jc_con, "jc_con", NULL, pcon_set, NULL, NULL);

static void pcon_save_fn(struct k_work *w)
{
	settings_save_one(PCON_KEY, &to_save, sizeof(to_save));
}
static K_WORK_DEFINE(pcon_save_work, pcon_save_fn);

static void pcon_forget_fn(struct k_work *w)
{
	settings_delete(PCON_KEY);
}
static K_WORK_DEFINE(pcon_forget_work, pcon_forget_fn);

void console_save(const bt_addr_le_t *addr, const uint8_t *ltk)
{
	to_save.ver = PCON_VER;
	bt_addr_le_copy(&to_save.addr, addr);
	memcpy(to_save.ltk, ltk, sizeof(to_save.ltk));
	k_work_submit(&pcon_save_work);
}

void console_forget(void)
{
	k_work_submit(&pcon_forget_work);
}

bool console_load(bt_addr_le_t *addr, uint8_t *ltk)
{
	loaded_ok = false;
	(void)settings_load_subtree("jc_con");
	if (!loaded_ok) {
		return false;
	}
	bt_addr_le_copy(addr, &loaded.addr);
	memcpy(ltk, loaded.ltk, sizeof(loaded.ltk));
	return true;
}

bool console_install(const bt_addr_le_t *addr, const uint8_t *ltk)
{
	struct bt_keys *k = bt_keys_get_addr(BT_ID_DEFAULT, addr);

	if (!k) {
		return false;
	}
	memset(&k->ltk, 0, sizeof(k->ltk));
	memcpy(k->ltk.val, ltk, 16);
	k->enc_size = 16;
	k->keys |= BT_KEYS_LTK_P256;
	k->flags |= BT_KEYS_AUTHENTICATED;
	return true;
}
```

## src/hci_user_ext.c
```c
#if defined(CONFIG_BT_CTLR_USER_EXT)

#include <zephyr/toolchain.h>
#include <zephyr/types.h>
#include <zephyr/net_buf.h>

#include "util/memq.h"

#include "ll_sw/pdu_df.h"
#include "lll/pdu_vendor.h"
#include "ll_sw/pdu.h"
#include "ll_sw/lll.h"
#include "hci/hci_user_ext.h"

int8_t hci_user_ext_get_class(struct node_rx_pdu *node_rx)
{
	ARG_UNUSED(node_rx);
	return 0;
}

void hci_user_ext_encode_control(struct node_rx_pdu *node_rx,
				 struct pdu_data *pdu_data, struct net_buf *buf)
{
	ARG_UNUSED(node_rx);
	ARG_UNUSED(pdu_data);
	ARG_UNUSED(buf);
}

#endif
```

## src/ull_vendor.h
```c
#if defined(CONFIG_BT_CTLR_USER_EXT)

static inline uint16_t ull_conn_interval_min_get(struct ll_conn *conn)
{
	ARG_UNUSED(conn);
	return 4U;
}

static inline int ull_user_init(void)
{
	return 0;
}

static inline int rx_demux_rx_proprietary(memq_link_t *link,
					  struct node_rx_hdr *rx,
					  memq_link_t *tail,
					  memq_link_t **head)
{
	ARG_UNUSED(link);
	ARG_UNUSED(rx);
	ARG_UNUSED(tail);
	ARG_UNUSED(head);
	return 0;
}

static inline void ull_proprietary_done(struct node_rx_event_done *evdone)
{
	ARG_UNUSED(evdone);
}

#endif
```

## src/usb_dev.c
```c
#include <zephyr/device.h>
#include <zephyr/init.h>
#include <zephyr/kernel.h>
#include <zephyr/usb/usbd.h>
#include <string.h>
#include <zephyr/usb/class/usbd_hid.h>

#define JC_USB_VID 0x2fe3
#define JC_USB_PID 0x0005

USBD_DEVICE_DEFINE(jc_usbd, DEVICE_DT_GET(DT_NODELABEL(zephyr_udc0)),
		   JC_USB_VID, JC_USB_PID);

USBD_DESC_LANG_DEFINE(jc_usb_lang);
USBD_DESC_MANUFACTURER_DEFINE(jc_usb_mfr, "XD2Joy");
USBD_DESC_PRODUCT_DEFINE(jc_usb_product, "XD2Joy (left)");
IF_ENABLED(CONFIG_HWINFO, (USBD_DESC_SERIAL_NUMBER_DEFINE(jc_usb_sn)));

USBD_DESC_CONFIG_DEFINE(jc_usb_fs_desc, "FS Configuration");

USBD_CONFIGURATION_DEFINE(jc_usb_fs_config, 0, 125, &jc_usb_fs_desc);

static const uint8_t jc_kbd_report_desc[] = HID_KEYBOARD_REPORT_DESC();

static bool jc_kbd_ready;

bool jc_usb_kbd_ready(void)
{
	return jc_kbd_ready;
}

static const struct device *jc_kbd_dev;
static uint8_t jc_kbd_wanted[8];
static uint8_t jc_kbd_sent[8];
static bool jc_kbd_inflight;
static struct k_spinlock jc_kbd_lock;

static bool jc_kbd_claim(void)
{
	k_spinlock_key_t key = k_spin_lock(&jc_kbd_lock);
	bool go = false;

	if (jc_kbd_ready && !jc_kbd_inflight &&
	    memcmp(jc_kbd_sent, jc_kbd_wanted, sizeof(jc_kbd_sent)) != 0) {
		memcpy(jc_kbd_sent, jc_kbd_wanted, sizeof(jc_kbd_sent));
		jc_kbd_inflight = true;
		go = true;
	}
	k_spin_unlock(&jc_kbd_lock, key);
	return go;
}

static void jc_kbd_pump(void)
{
	k_spinlock_key_t key;

	if (!jc_kbd_claim()) {
		return;
	}
	if (hid_device_submit_report(jc_kbd_dev, sizeof(jc_kbd_sent),
				     jc_kbd_sent) == 0) {
		return;
	}

	key = k_spin_lock(&jc_kbd_lock);
	jc_kbd_inflight = false;
	memset(jc_kbd_sent, 0xFF, sizeof(jc_kbd_sent));
	k_spin_unlock(&jc_kbd_lock, key);
}

static void jc_kbd_report_done(const struct device *dev,
			       const uint8_t *const report)
{
	ARG_UNUSED(dev);
	ARG_UNUSED(report);

	k_spinlock_key_t key = k_spin_lock(&jc_kbd_lock);

	jc_kbd_inflight = false;
	k_spin_unlock(&jc_kbd_lock, key);
	jc_kbd_pump();
}

void jc_usb_kbd_send(uint8_t mods, const uint8_t keys[6])
{
	k_spinlock_key_t key = k_spin_lock(&jc_kbd_lock);

	jc_kbd_wanted[0] = mods;
	jc_kbd_wanted[1] = 0;
	memcpy(&jc_kbd_wanted[2], keys, 6);
	k_spin_unlock(&jc_kbd_lock, key);
	jc_kbd_pump();
}

void jc_usb_kbd_release_all(void)
{
	static const uint8_t none[6] = { 0 };

	jc_usb_kbd_send(0, none);
}

static void jc_kbd_iface_ready(const struct device *dev, const bool ready)
{
	ARG_UNUSED(dev);
	jc_kbd_ready = ready;
}

static int jc_kbd_get_report(const struct device *dev, const uint8_t type,
			     const uint8_t id, const uint16_t len,
			     uint8_t *const buf)
{
	ARG_UNUSED(dev);
	ARG_UNUSED(type);
	ARG_UNUSED(id);
	memset(buf, 0, len);
	return 0;
}

static int jc_kbd_set_report(const struct device *dev, const uint8_t type,
			     const uint8_t id, const uint16_t len,
			     const uint8_t *const buf)
{
	ARG_UNUSED(dev);
	ARG_UNUSED(id);
	ARG_UNUSED(len);
	ARG_UNUSED(buf);
	if (type != HID_REPORT_TYPE_OUTPUT) {
		return -ENOTSUP;
	}
	return 0;
}

static void jc_kbd_set_protocol(const struct device *dev, const uint8_t proto)
{
	ARG_UNUSED(dev);
}

static struct hid_device_ops jc_kbd_ops = {
	.iface_ready = jc_kbd_iface_ready,
	.get_report = jc_kbd_get_report,
	.set_report = jc_kbd_set_report,
	.set_protocol = jc_kbd_set_protocol,
	.input_report_done = jc_kbd_report_done,
};

static int jc_usb_init(void)
{
	const struct device *hid = DEVICE_DT_GET(DT_NODELABEL(jc_hid_kbd));
	bool kbd_ok = false;
	int err;

	if (device_is_ready(hid)) {
		err = hid_device_register(hid, jc_kbd_report_desc,
					  sizeof(jc_kbd_report_desc),
					  &jc_kbd_ops);
		if (!err) {
			jc_kbd_dev = hid;
			kbd_ok = true;
		}
	}

	err = usbd_add_descriptor(&jc_usbd, &jc_usb_lang);
	if (!err) {
		err = usbd_add_descriptor(&jc_usbd, &jc_usb_mfr);
	}
	if (!err) {
		err = usbd_add_descriptor(&jc_usbd, &jc_usb_product);
	}
	IF_ENABLED(CONFIG_HWINFO, (
		if (!err) {
			err = usbd_add_descriptor(&jc_usbd, &jc_usb_sn);
		}
	))
	if (err) {
		return err;
	}

	err = usbd_add_configuration(&jc_usbd, USBD_SPEED_FS, &jc_usb_fs_config);
	if (err) {
		return err;
	}

	err = usbd_register_class(&jc_usbd, "cdc_acm_0", USBD_SPEED_FS, 1);
	if (err) {
		return err;
	}

	if (kbd_ok) {
		err = usbd_register_class(&jc_usbd, "hid_0", USBD_SPEED_FS, 1);
	}

	err = usbd_device_set_code_triple(&jc_usbd, USBD_SPEED_FS,
					  USB_BCC_MISCELLANEOUS, 0x02, 0x01);
	if (err) {
		return err;
	}

	err = usbd_init(&jc_usbd);
	if (err) {
		return err;
	}

	return usbd_enable(&jc_usbd);
}

SYS_INIT(jc_usb_init, APPLICATION, CONFIG_APPLICATION_INIT_PRIORITY);
```

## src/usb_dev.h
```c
#ifndef JC_USB_DEV_H
#define JC_USB_DEV_H

#include <stdbool.h>
#include <stdint.h>

bool jc_usb_kbd_ready(void);

void jc_usb_kbd_send(uint8_t mods, const uint8_t keys[6]);

void jc_usb_kbd_release_all(void);

#endif
```
